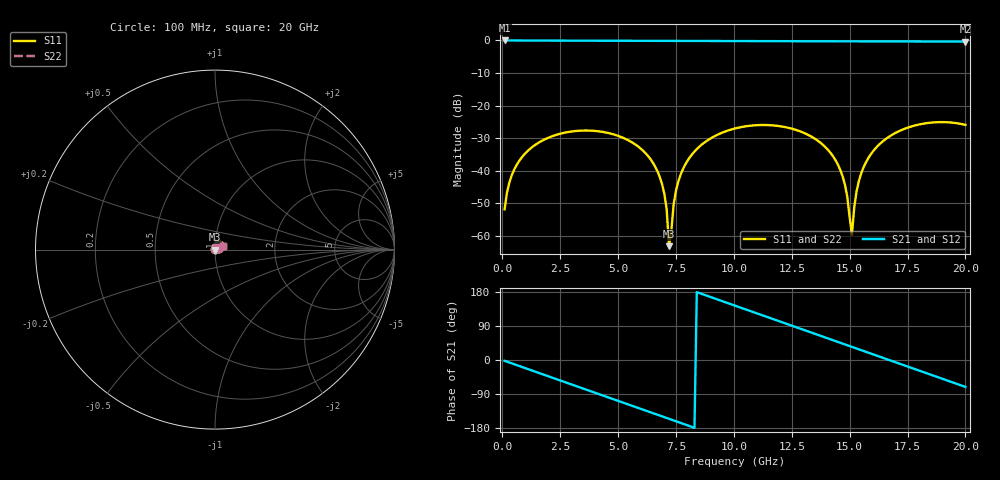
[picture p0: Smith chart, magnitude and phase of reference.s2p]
! circuitRF F0 spike reference -- case B, Palace, lines as zero-thickness sheets with Thickness 35 um (Q6)
! Palace postpro/port-S.csv, dB/deg -> RI; port 1 excited only; S22 = S11 and S12 = S21 by the 180-degree rotational symmetry of the geometry
# GHz S RI R 50
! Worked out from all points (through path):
!   200 points, 100 MHz to 20 GHz, reference 50 ohm
!   highest |S21| = -0.01 dB at 100 MHz (marker M1); lowest = -0.4 dB at 20 GHz (marker M2)
!   group delay of S21, straight-line fit = 59.8 ps
!   lowest |S11| = -63.1 dB at 7.2 GHz (marker M3), VSWR 1.00, Z = 50 - j0.06 ohm
!   |S11| at or under -10 dB: start of sweep to end of sweep
!   |S22| runs from -63.1 to -25.0 dB; largest |S21 - S12| = 0
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0.1  0.000745 0.00247  0.9985 -0.0384  0.9985 -0.0384  0.000745 0.00247
0.4  0.00258 0.00799  0.9866 -0.1511  0.9866 -0.1511  0.00258 0.00799
1  0.00875 0.0165  0.926 -0.368  0.926 -0.368  0.00875 0.0165
3.5  0.0407 0.00813  0.2477 -0.9594  0.2477 -0.9594  0.0407 0.00813
5.6  0.023 -0.0149  -0.5041 -0.8487  -0.5041 -0.8487  0.023 -0.0149
6.8  0.00428 -0.00685  -0.8218 -0.5429  -0.8218 -0.5429  0.00428 -0.00685
7.1  0.00117 -0.00228  -0.8771 -0.4467  -0.8771 -0.4467  0.00117 -0.00228
7.2  0.000364 -0.000599  -0.8931 -0.4133  -0.8931 -0.4133  0.000364 -0.000599
7.5  -0.0013 0.00478  -0.9333 -0.3099  -0.9333 -0.3099  -0.0013 0.00478
7.9  -0.0016 0.0124  -0.9682 -0.1665  -0.9682 -0.1665  -0.0016 0.0124
8.8  0.0057 0.0278  -0.9664 0.1638  -0.9664 0.1638  0.0057 0.0278
10.1  0.0286 0.0349  -0.7741 0.5956  -0.7741 0.5956  0.0286 0.0349
11.8  0.0479 0.0122  -0.2667 0.9359  -0.2667 0.9359  0.0479 0.0122
13.4  0.0307 -0.0114  0.3083 0.9206  0.3083 0.9206  0.0307 -0.0114
14.6  0.00664 -0.00784  0.678 0.6927  0.678 0.6927  0.00664 -0.00784
14.9  0.0017 -0.00361  0.7514 0.6116  0.7514 0.6116  0.0017 -0.00361
15.1  -0.00104 -0.000187  0.7951 0.5531  0.7951 0.5531  -0.00104 -0.000187
15.3  -0.00325 0.00362  0.8342 0.4915  0.8342 0.4915  -0.00325 0.00362
15.5  -0.0049 0.00773  0.8685 0.4271  0.8685 0.4271  -0.0049 0.00773
16.7  -0.00141 0.0333  0.9654 0.00458  0.9654 0.00458  -0.00141 0.0333
18.2  0.0265 0.046  0.8151 -0.5115  0.8151 -0.5115  0.0265 0.046
20  0.0469 0.0194  0.3127 -0.9073  0.3127 -0.9073  0.0469 0.0194
